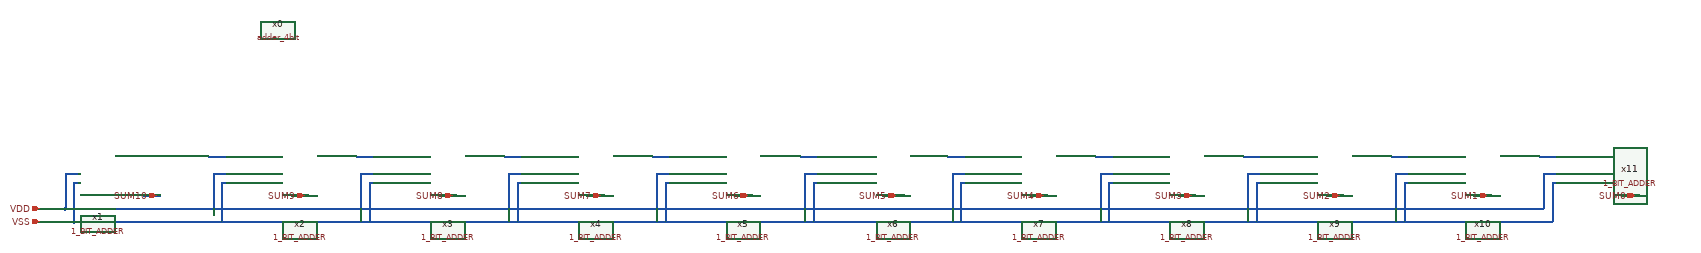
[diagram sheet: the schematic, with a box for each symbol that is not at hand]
v {xschem version=3.4.4 file_version=1.2
}
G {}
K {}
V {}
S {}
E {}
N 3540 -180 3570 -180 {
lab=#net1}
N 3530 -180 3540 -180 {
lab=#net1}
N 3190 -180 3230 -180 {
lab=#net2}
N 2850 -180 2890 -180 {
lab=#net3}
N 2510 -180 2550 -180 {
lab=#net4}
N 2170 -180 2210 -180 {
lab=#net5}
N 1830 -180 1870 -180 {
lab=#net6}
N 1490 -180 1530 -180 {
lab=#net7}
N 1150 -180 1190 -180 {
lab=#net8}
N 810 -180 850 -180 {
lab=#net9}
N 470 -180 510 -180 {
lab=#net10}
N 70 -60 120 -60 {
lab=VDD}
N 120 -60 130 -60 {
lab=VDD}
N 130 -60 140 -60 {
lab=VDD}
N 140 -140 140 -60 {
lab=VDD}
N 140 -140 170 -140 {
lab=VDD}
N 70 -30 140 -30 {
lab=VSS}
N 140 -30 150 -30 {
lab=VSS}
N 150 -30 160 -30 {
lab=VSS}
N 160 -120 160 -30 {
lab=VSS}
N 160 -120 170 -120 {
lab=VSS}
N 140 -60 3540 -60 {
lab=VDD}
N 3540 -140 3540 -60 {
lab=VDD}
N 3540 -140 3570 -140 {
lab=VDD}
N 160 -30 3560 -30 {
lab=VSS}
N 3560 -110 3560 -30 {
lab=VSS}
N 3560 -120 3560 -110 {
lab=VSS}
N 3560 -120 3570 -120 {
lab=VSS}
N 500 -120 510 -120 {
lab=VSS}
N 500 -120 500 -30 {
lab=VSS}
N 480 -140 510 -140 {
lab=VDD}
N 480 -140 480 -60 {
lab=VDD}
N 840 -120 850 -120 {
lab=VSS}
N 840 -120 840 -30 {
lab=VSS}
N 820 -140 850 -140 {
lab=VDD}
N 820 -140 820 -60 {
lab=VDD}
N 1180 -120 1190 -120 {
lab=VSS}
N 1180 -120 1180 -30 {
lab=VSS}
N 1160 -140 1190 -140 {
lab=VDD}
N 1520 -120 1530 -120 {
lab=VSS}
N 1520 -120 1520 -30 {
lab=VSS}
N 1500 -140 1530 -140 {
lab=VDD}
N 1500 -140 1500 -60 {
lab=VDD}
N 1160 -140 1160 -60 {
lab=VDD}
N 1860 -120 1870 -120 {
lab=VSS}
N 1860 -120 1860 -30 {
lab=VSS}
N 1840 -140 1870 -140 {
lab=VDD}
N 1840 -140 1840 -60 {
lab=VDD}
N 2200 -120 2210 -120 {
lab=VSS}
N 2200 -120 2200 -30 {
lab=VSS}
N 2180 -140 2210 -140 {
lab=VDD}
N 2180 -140 2180 -60 {
lab=VDD}
N 2540 -120 2550 -120 {
lab=VSS}
N 2540 -120 2540 -30 {
lab=VSS}
N 2520 -140 2550 -140 {
lab=VDD}
N 2520 -140 2520 -60 {
lab=VDD}
N 2880 -120 2890 -120 {
lab=VSS}
N 2880 -120 2880 -30 {
lab=VSS}
N 2860 -140 2890 -140 {
lab=VDD}
N 2860 -140 2860 -60 {
lab=VDD}
N 3220 -120 3230 -120 {
lab=VSS}
N 3220 -120 3220 -30 {
lab=VSS}
N 3200 -140 3230 -140 {
lab=VDD}
N 3200 -140 3200 -60 {
lab=VDD}
N 320 -90 360 -90 {
lab=SUM10}
N 660 -90 700 -90 {
lab=SUM9}
N 1000 -90 1040 -90 {
lab=SUM8}
N 1340 -90 1380 -90 {
lab=SUM7}
N 1680 -90 1720 -90 {
lab=SUM6}
N 2020 -90 2070 -90 {
lab=SUM5}
N 2360 -90 2400 -90 {
lab=SUM4}
N 2700 -90 2740 -90 {
lab=SUM3}
N 3040 -90 3080 -90 {
lab=SUM2}
N 3380 -90 3420 -90 {
lab=SUM1}
N 3720 -90 3760 -90 {
lab=SUM0}
C {CNR_GR03_SKY130NM/1_BIT_ADDER.sym} 320 -180 0 0 {name=x1}
C {CNR_GR03_SKY130NM/1_BIT_ADDER.sym} 660 -180 0 0 {name=x2}
C {CNR_GR03_SKY130NM/1_BIT_ADDER.sym} 1000 -180 0 0 {name=x3}
C {CNR_GR03_SKY130NM/1_BIT_ADDER.sym} 1340 -180 0 0 {name=x4}
C {CNR_GR03_SKY130NM/1_BIT_ADDER.sym} 1680 -180 0 0 {name=x5}
C {CNR_GR03_SKY130NM/1_BIT_ADDER.sym} 2020 -180 0 0 {name=x6}
C {CNR_GR03_SKY130NM/1_BIT_ADDER.sym} 2360 -180 0 0 {name=x7}
C {CNR_GR03_SKY130NM/1_BIT_ADDER.sym} 2700 -180 0 0 {name=x8}
C {CNR_GR03_SKY130NM/1_BIT_ADDER.sym} 3040 -180 0 0 {name=x9}
C {CNR_GR03_SKY130NM/1_BIT_ADDER.sym} 3380 -180 0 0 {name=x10}
C {CNR_GR03_SKY130NM/1_BIT_ADDER.sym} 3720 -180 0 0 {name=x11}
C {devices/iopin.sym} 80 -60 2 0 {name=p1 lab=VDD}
C {devices/iopin.sym} 80 -30 2 0 {name=p2 lab=VSS}
C {devices/iopin.sym} 350 -90 0 0 {name=p3 lab=SUM10}
C {devices/iopin.sym} 690 -90 0 0 {name=p4 lab=SUM9}
C {devices/iopin.sym} 1030 -90 0 0 {name=p5 lab=SUM8}
C {devices/iopin.sym} 1370 -90 0 0 {name=p6 lab=SUM7}
C {devices/iopin.sym} 1710 -90 0 0 {name=p7 lab=SUM6}
C {devices/iopin.sym} 2050 -90 0 0 {name=p8 lab=SUM5}
C {devices/iopin.sym} 2390 -90 0 0 {name=p9 lab=SUM4}
C {devices/iopin.sym} 2730 -90 0 0 {name=p10 lab=SUM3}
C {devices/iopin.sym} 3070 -90 0 0 {name=p11 lab=SUM2}
C {devices/iopin.sym} 3410 -90 0 0 {name=p12 lab=SUM1}
C {devices/iopin.sym} 3750 -90 0 0 {name=p13 lab=SUM0}
C {sky130_tests/adder_4bit.sym} 630 -470 0 0 {name=x0}
